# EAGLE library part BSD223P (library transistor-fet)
OptiMOS(R)-P Small-Signal-Transistor Dual P-Channel, Enhancement mode, Super Logic Level (2.5 V rated) Source: http://www.infineon.com/upload/Document/BSD223P_Rev1.3.pdf

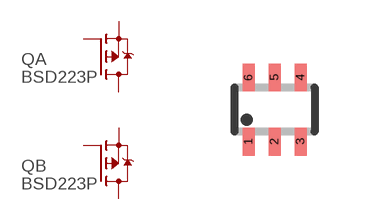
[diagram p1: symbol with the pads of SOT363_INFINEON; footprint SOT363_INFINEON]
Designator prefix Q; gates A=P-MOSFET B=P-MOSFET

## BSD223P  [SOT363_INFINEON]
1  A:S  pas
2  A:G  pas
3  B:D  pas
4  B:S  pas
5  B:G  pas
6  A:D  pas

## Footprint SOT363_INFINEON (pad centres in mm)
Small Outline Transistor; 6 leads Reflow soldering INFINEON, www.infineon.com/cmc_upload/0/000/010/257/eh_db_5b.pdf
smd 0.3 x 0.7: 1 -0.65,-0.8; 2 0,-0.8; 3 0.65,-0.8; 4 0.65,0.8; 5 0,0.8; 6 -0.65,0.8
